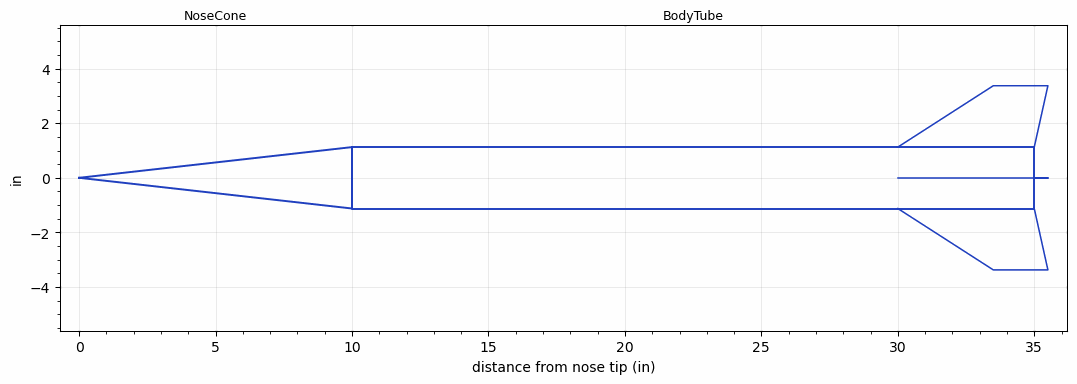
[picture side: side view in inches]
<RASAeroDocument>
 <FileVersion>2</FileVersion>
 <RocketDesign>
  <NoseCone>
   <Length>10</Length>
   <Diameter>2.25</Diameter>
   <Shape>Conical</Shape>
   <Location>0</Location>
  </NoseCone>
  <BodyTube>
   <Length>25</Length>
   <Diameter>2.25</Diameter>
   <Location>10</Location>
   <Fin>
    <Count>4</Count>
    <Chord>5</Chord>
    <Span>2.25</Span>
    <SweepDistance>3.5</SweepDistance>
    <TipChord>2</TipChord>
    <Thickness>0.125</Thickness>
    <LERadius>0.024</LERadius>
    <Location>5</Location>
    <AirfoilSection>Double Wedge</AirfoilSection>
    <FX1>1</FX1>
    <FX3>1</FX3>
   </Fin>
  </BodyTube>
  <Surface>Rough Camouflage Paint</Surface>
  <ModifiedBarrowman>False</ModifiedBarrowman>
  <Turbulence>False</Turbulence>
  <UseBooster1>False</UseBooster1>
  <UseBooster2>False</UseBooster2>
 </RocketDesign>
 <LaunchSite>
  <Altitude>4000</Altitude>
  <Pressure>29.9</Pressure>
  <RodAngle>5</RodAngle>
  <RodLength>10</RodLength>
  <Temperature>90</Temperature>
  <WindSpeed>5</WindSpeed>
 </LaunchSite>
 <Recovery>
  <Altitude1>1000</Altitude1>
  <Altitude2>1000</Altitude2>
  <DeviceType1>None</DeviceType1>
  <DeviceType2>None</DeviceType2>
  <Event1>False</Event1>
  <Event2>False</Event2>
  <Size1>1</Size1>
  <Size2>1</Size2>
  <EventType1>None</EventType1>
  <EventType2>None</EventType2>
  <CD1>1.33</CD1>
  <CD2>1.33</CD2>
 </Recovery>
 <SimulationList>
  <Simulation>
   <SustainerEngine>L1785(L+N+P)  (Polaris)</SustainerEngine>
   <SustainerLaunchWt>7.6</SustainerLaunchWt>
   <SustainerNozzleDiameter>2.25</SustainerNozzleDiameter>
   <SustainerCG>21.6</SustainerCG>
   <SustainerIgnitionDelay>0</SustainerIgnitionDelay>
   <Booster1SeparationDelay>0</Booster1SeparationDelay>
   <Booster1IgnitionDelay>0</Booster1IgnitionDelay>
   <IncludeBooster1>False</IncludeBooster1>
   <Booster2Delay>0</Booster2Delay>
   <IncludeBooster2>False</IncludeBooster2>
   <TimetoApogee>42.06895</TimetoApogee>
   <MaxAltitude>43456.98</MaxAltitude>
   <MaxVelocity>4509.052</MaxVelocity>
   <OptimumWt>7.8375</OptimumWt>
   <OptimumMaxAlt>7.8375</OptimumMaxAlt>
  </Simulation>
 </SimulationList>
</RASAeroDocument>
